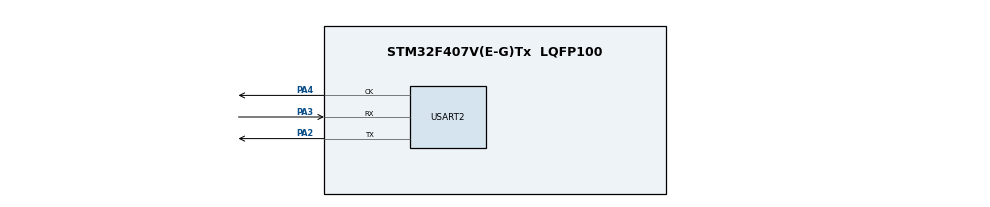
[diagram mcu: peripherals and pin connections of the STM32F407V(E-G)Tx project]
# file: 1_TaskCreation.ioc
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FREERTOS.Tasks01=defaultTask,24,128,StartDefaultTask,Default,NULL,Dynamic,NULL,NULL
Mcu.Family=STM32F4
Mcu.Name=STM32F407V(E-G)Tx
Mcu.Package=LQFP100
NVIC.PriorityGroup=NVIC_PRIORITYGROUP_4
PA2.Mode=Synchronous
PA2.Signal=USART2_TX
PA3.Mode=Synchronous
PA3.Signal=USART2_RX
PA4.Mode=Synchronous
PA4.Signal=USART2_CK
PC14-OSC32_IN.Mode=LSE-External-Oscillator
PC14-OSC32_IN.Signal=RCC_OSC32_IN
PC15-OSC32_OUT.Mode=LSE-External-Oscillator
PC15-OSC32_OUT.Signal=RCC_OSC32_OUT
PH0-OSC_IN.Mode=HSE-External-Clock-Source
PH0-OSC_IN.Signal=RCC_OSC_IN
PH1-OSC_OUT.Mode=HSE-External-Clock-Source
PH1-OSC_OUT.Signal=RCC_OSC_OUT
ProjectManager.HeapSize=0x200
ProjectManager.StackSize=0x400
ProjectManager.TargetToolchain=STM32CubeIDE
RCC.48MHZClocksFreq_Value=48000000
RCC.AHBFreq_Value=168000000
RCC.APB1CLKDivider=RCC_HCLK_DIV4
RCC.APB1Freq_Value=42000000
RCC.APB1TimFreq_Value=84000000
RCC.APB2CLKDivider=RCC_HCLK_DIV2
RCC.APB2Freq_Value=84000000
RCC.APB2TimFreq_Value=168000000
RCC.CortexFreq_Value=168000000
RCC.HCLKFreq_Value=168000000
RCC.HSE_VALUE=8000000
RCC.HSI_VALUE=16000000
RCC.PLLM=8
RCC.PLLN=336
RCC.PLLQ=7
RCC.PLLSourceVirtual=RCC_PLLSOURCE_HSE
RCC.SYSCLKFreq_VALUE=168000000
RCC.SYSCLKSource=RCC_SYSCLKSOURCE_PLLCLK
RCC.VCOOutputFreq_Value=336000000
USART2.VirtualMode=VM_SYNC
VP_FREERTOS_VS_CMSIS_V2.Mode=CMSIS_V2
board=STM32F407G-DISC1

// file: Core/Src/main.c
#include <stdio.h>
#include "main.h"
#include "cmsis_os.h"
/*To enable semaphore include "semphr.h" in "cmsis_os.h"*/
TaskHandle_t  blue_handler,red_handler,yellow_handler;
int blue, red, yellow;
USART_HandleTypeDef husart2;
SemaphoreHandle_t Mutex;

int _io__putchar( int ch);
int uart2_write( int ch );

/*function prototypes -----------------------------------------------*/
void SystemClock_Config(void);
static void MX_GPIO_Init(void);
static void MX_USART2_Init(void);
void blue_led(void *PvParameters);
void red_led(void *PvParameters);

int main(void)
{
  HAL_Init();
  SystemClock_Config();
  MX_GPIO_Init();
  MX_USART2_Init();

  /* Create mutex for mutual exclusion */
  Mutex = xSemaphoreCreateMutex();

  xTaskCreate(blue_led, "senderTask1",100,NULL, 1, &blue_handler);
  xTaskCreate(red_led, "senderTask2",100,NULL, 1, &red_handler);

  vTaskStartScheduler();
  while (1)
  {

  }

}

void blue_led ( void *pVparameters)
{
	while(1)
	{
		// Try to take the mutex within 5 RTOS ticks (e.g., 5 ms if tick rate = 1 kHz)
		// If successful, enter the critical section; else, skip this attempt
		if(xSemaphoreTake(Mutex,(TickType_t) 5) == pdTRUE)
		{
			printf("This is blue task....\r\n");
			// Release the mutex
			xSemaphoreGive(Mutex);
		}
		vTaskDelay(1);
	}
}

void red_led ( void *pVparameters)
{
	while(1)
    {
		// Try to take the mutex within 5 RTOS ticks (e.g., 5 ms if tick rate = 1 kHz)
		// If successful, enter the critical section; else, skip this attempt
		if(xSemaphoreTake(Mutex,(TickType_t) 5) == pdTRUE)
		{
			printf("This is red task....\r\n");
			// Release the mutex
			xSemaphoreGive(Mutex);
		}
		vTaskDelay(1);
    }
}

// Function to send a byte via USART2
int uart2_write( int ch )
{
	/*Wait until Transmit Data Register Empty (TXE = 1)
	  While TXE is 0, it means the previous data has not yet been moved
	*/
	while( !(USART2->SR & 0x0080)){}

	//Write the lower 8 bits of 'ch' into the Data Register (DR) for transmission
	USART2-> DR = ( ch & 0xFF );
	return ch;
}

int _io__putchar( int ch)
{
	uart2_write( ch);
	return ch;
}

void SystemClock_Config(void)
{
  RCC_OscInitTypeDef RCC_OscInitStruct = {0};
  RCC_ClkInitTypeDef RCC_ClkInitStruct = {0};

  /** Configure the main internal regulator output voltage
  */
  __HAL_RCC_PWR_CLK_ENABLE();
  __HAL_PWR_VOLTAGESCALING_CONFIG(PWR_REGULATOR_VOLTAGE_SCALE1);

  /** Initializes the RCC Oscillators according to the specified parameters
  * in the RCC_OscInitTypeDef structure.
  */
  RCC_OscInitStruct.OscillatorType = RCC_OSCILLATORTYPE_HSI;
  RCC_OscInitStruct.HSIState = RCC_HSI_ON;
  RCC_OscInitStruct.HSICalibrationValue = RCC_HSICALIBRATION_DEFAULT;
  RCC_OscInitStruct.PLL.PLLState = RCC_PLL_ON;
  RCC_OscInitStruct.PLL.PLLSource = RCC_PLLSOURCE_HSI;
  RCC_OscInitStruct.PLL.PLLM = 8;
  RCC_OscInitStruct.PLL.PLLN = 50;
  RCC_OscInitStruct.PLL.PLLP = RCC_PLLP_DIV4;
  RCC_OscInitStruct.PLL.PLLQ = 7;
  if (HAL_RCC_OscConfig(&RCC_OscInitStruct) != HAL_OK)
  {
    Error_Handler();
  }

  /** Initializes the CPU, AHB and APB buses clocks
  */
  RCC_ClkInitStruct.ClockType = RCC_CLOCKTYPE_HCLK|RCC_CLOCKTYPE_SYSCLK
                              |RCC_CLOCKTYPE_PCLK1|RCC_CLOCKTYPE_PCLK2;
  RCC_ClkInitStruct.SYSCLKSource = RCC_SYSCLKSOURCE_PLLCLK;
  RCC_ClkInitStruct.AHBCLKDivider = RCC_SYSCLK_DIV1;
  RCC_ClkInitStruct.APB1CLKDivider = RCC_HCLK_DIV4;
  RCC_ClkInitStruct.APB2CLKDivider = RCC_HCLK_DIV2;

  if (HAL_RCC_ClockConfig(&RCC_ClkInitStruct, FLASH_LATENCY_0) != HAL_OK)
  {
    Error_Handler();
  }
}

static void MX_USART2_Init(void)
{

  husart2.Instance = USART2;
  husart2.Init.BaudRate = 115200;
  husart2.Init.WordLength = USART_WORDLENGTH_8B;
  husart2.Init.StopBits = USART_STOPBITS_1;
  husart2.Init.Parity = USART_PARITY_NONE;
  husart2.Init.Mode = USART_MODE_TX_RX;
  husart2.Init.CLKPolarity = USART_POLARITY_LOW;
  husart2.Init.CLKPhase = USART_PHASE_1EDGE;
  husart2.Init.CLKLastBit = USART_LASTBIT_DISABLE;
  if (HAL_USART_Init(&husart2) != HAL_OK)
  {
    Error_Handler();
  }

}

static void MX_GPIO_Init(void)
{

  /* GPIO Ports Clock Enable */
  __HAL_RCC_GPIOA_CLK_ENABLE();

}

void Error_Handler(void)
{
  __disable_irq();
  while (1)
  {
  }
}
